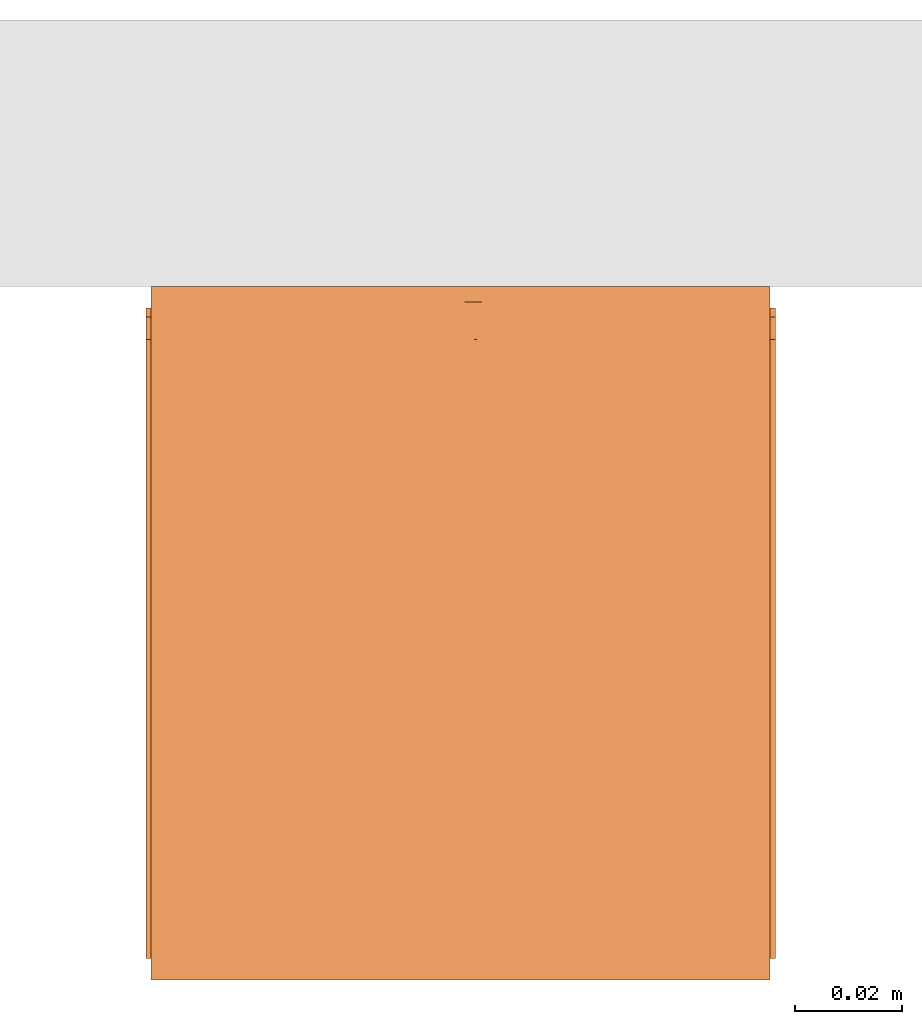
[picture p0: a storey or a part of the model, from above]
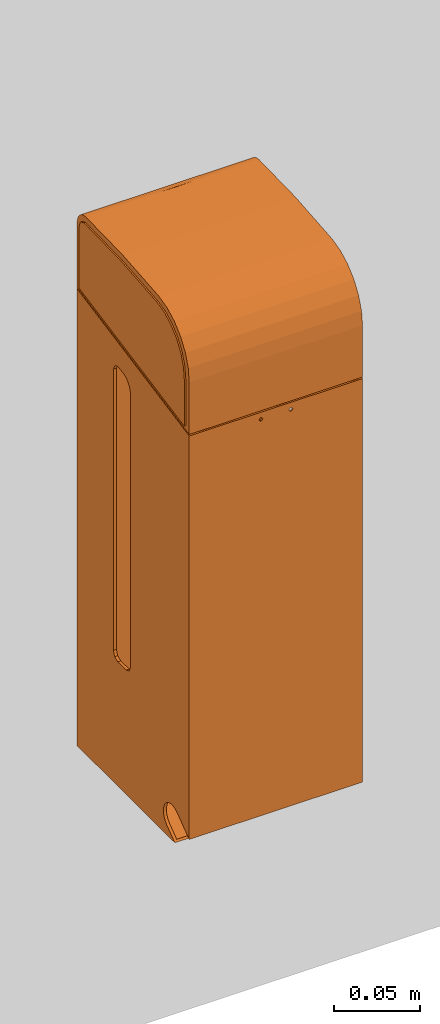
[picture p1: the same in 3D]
Properties of the parts of a building model (IFC2X3)

# File
Description: ViewDefinition [CoordinationView]
Time: 2018-01-17T15:09:57
Written by: The EXPRESS Data Manager Version 5.01.0100.02.64mod : 6 Jun 2012
Made in: 20140709_2115(x64) - Exporter 2014.0.2014.0709 - Default UI
Comment: STEP Physical File produced by: The EXPRESS Data Manager Version 5.01.0100.02.64mod : 6 Jun 2012 * Module: EDMstepFileFactory/EDMstandAlone * Creation date: Wed Jan 17 15:09:57 2018 * Host: BIM-HP * Database: C:\Users\dcole\AppData\Local\Temp\{F9AC8313-FCF2-4634-B228-EDCF961F2BBE}\ifc * Database version: 5507 * Database creation date: Wed Jan 17 15:09:56 2018 * Schema: IFC2X3 * Model: DataRepository.ifc * Model creation date: Wed Jan 17 15:09:56 2018 * Header model: DataRepository.ifc_HeaderModel * Header model creation date: Wed Jan 17 15:09:56 2018 * EDMuser: sdai-user * EDMgroup: sdai-group * License ID and type: 5605 : Permanent license. Expiry date: * EDMstepFileFactory options: 020000

# IfcProject
LongName: P:\Fastrack\53721_DOLPHIN SOLUTIONS LIMITED\ADDITIONAL DRAWINGS 2018 BIM\IFC\BC707-3SS.ifc

# IfcSite, Default
RefLatitude: 42, 24, 53, 508911; RefLongitude: -71, -15, -29, -58837; RefElevation: 0 mm

# IfcBuilding
Pset_BuildingCommon - NumberOfStoreys: 1

# IfcBuildingStorey, Level 1
LongName: Level 1; Elevation: 0 mm
Constraints - Elevation Base: Project Base Point; Elevation: 0 mm
Identity Data - Name: Level 1; Structural: no; Building Story: yes
Dimensions - Computation Height: 0 mm
Graphics - Line Pattern: -3000010; Line Weight: 1; Color: 0; Symbol at End 1 Default: no; Symbol at End 2 Default: yes

# IfcBuildingElementProxy: BC707-3SS Dolphin Three Roll Toilet Roll Holder, BC707-3SS:BC707-3SS Dolphin Three Roll Toilet Roll Holder:72511
In: Level 1
Dimensions - Volume: 0.000325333 m3; Projection: 130mm; Width: 116mm; Height: 380mm
Constraints - Offset: 212.697 mm; Level: Level: Level 1; Host: Level : Level 1; Moves With Nearby Elements: no
Phasing - Phase Created: New Construction
Pset_ManufacturerTypeInformation - Manufacturer: Dolphin Solutions Ltd.
Pset_BuildingElementProxyCommon - Reference: BC707-3SS Dolphin Three Roll Toilet Roll Holder
Identity Data - Fax No.: +44 (0) 1424 205 200; Description: Three roll toilet roll holder; Assembly Description: Other Plumbing Fixtures; URL: www.dolphinsolutions.co.uk; Email: info@dolphinsolutions.co.uk; Tel No.: +44 (0) 1424 202 224; Model: BC707-3SS; Address: Southpoint, Compass Park, Bodiam, Robertsbridge, TN32 5BS; Manufacturer: Dolphin Solutions Ltd.; Assembly Code: D2010900
General - Product Page Link: https://www.dolphinsolutions.co.uk/en/product/3-roll-toilet-roll-holder/; Product Data: Quality stainless steel construction. Lockable. Dispenses quality toilet rolls up to a maximum of 125mm diameter and 110mm wide. Holds three standard toilet rolls. Vandal Restant. Ideal for schools, restaurants, offices, council and commercial premises. Recommended install height from base to floor is 65-75cm.

# IfcWallStandardCase: Basic Wall:Wall 1, Basic Wall:Wall 1:3092
In: Level 1
Type - PredefinedType: STANDARD; Material: Default Wall 50 mm
Type - Analytical Properties - Roughness: 1; Absorptance: 0.1
Type - Graphics - Coarse Scale Fill Color: 8454143
Type - Construction - Width: 50 mm; Function: Exterior; Wrapping at Inserts: Do not wrap
Constraints - Location Line: Finish Face: Interior; Top Offset: 0 mm; Base Constraint: Level: Level 1; Unconnected Height: 936.967 mm; Related to Mass: no; Top is Attached: no; Top Extension Distance: 0 mm; Base Offset: 0 mm; Room Bounding: yes; Base Extension Distance: 0 mm; Base is Attached: no
Structural - Enable Analytical Model: no; Structural Usage: Non-bearing; Structural: no
Dimensions - Length: 640 mm; Volume: 0.0299829 m3; Area: 0.599659 m2
Phasing - Phase Created: New Construction
Pset_WallCommon - Reference: Wall 1; LoadBearing: no; ExtendToStructure: no; IsExternal: yes
